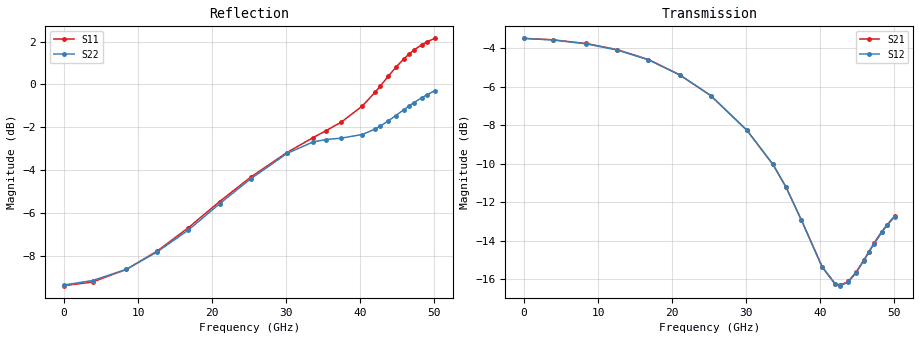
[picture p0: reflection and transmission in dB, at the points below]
! Touchstone file from project
! Exported from ElectronicsDesktop 2025.1.3
# GHz S MA R 50.000000
! Terminal data exported
! Port[1] = Port1
! Port[2] = Port2
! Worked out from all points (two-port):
!   144 points, 10 MHz to 50.05 GHz, reference 50 ohm
!   highest |S21| = -3.50 dB at 10 MHz (marker M1); lowest = -16.3 dB at 42.7 GHz (marker M2)
!   |S21| within 3 dB of the highest: start of sweep to 25.31 GHz
!   lowest |S11| = -9.4 dB at 10 MHz (marker M3), VSWR 2.02, Z = 101 - j0.545 ohm
!   |S11| at or under -10 dB: nowhere
!   |S22| runs from -9.4 to -0.3 dB; largest |S21 - S12| = 0.0023
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0.01  0.3384 -0.4  0.6686 -5.8  0.6682 -6.0  0.3396 0.2
! Gamma 0 0 0 0
! Port Impedance 50 0 50 0
3.85945  0.3452 -1.3  0.663 -10.2  0.6623 -10.3  0.3479 -0.2
8.4088  0.3693 -3.1  0.6484 -19.0  0.647 -18.9  0.3694 -1.7
12.6082  0.408 -4.8  0.6249 -28.5  0.6234 -28.5  0.4062 -2.7
16.8076  0.4625 -7.4  0.5891 -38.2  0.5881 -38.3  0.4568 -4.8
21.007  0.5323 -11.0  0.5378 -48.1  0.5375 -48.1  0.526 -8.3
25.2064  0.607 -16.4  0.475 -57.9  0.4751 -57.9  0.6016 -13.2
30.1057  0.6933 -23.9  0.3857 -67.9  0.3858 -67.9  0.6897 -21.0
33.6052  0.7508 -29.4  0.3147 -73.1  0.3146 -73.1  0.7335 -26.8
35.35495  0.7793 -32.1  0.2752 -74.1  0.2751 -74.2  0.7434 -29.7
37.45465  0.8169 -35.2  0.2256 -72.0  0.2253 -72.1  0.7492 -32.9
40.25425  0.8898 -39.1  0.1706 -59.6  0.1702 -59.7  0.7638 -36.6
42.004  0.9591 -40.8  0.1543 -46.6  0.1537 -46.7  0.7866 -38.5
42.7039  0.9918 -41.1  0.153 -41.0  0.1524 -41.1  0.7992 -38.9
43.75375  1.044 -40.7  0.1563 -32.9  0.1556 -33.0  0.8213 -39.0
44.8036  1.097 -39.3  0.1651 -26.0  0.1643 -26.1  0.8462 -38.2
45.85345  1.147 -36.7  0.1775 -21.1  0.1766 -21.2  0.8724 -36.4
46.55335  1.177 -34.3  0.1868 -19.2  0.186 -19.2  0.8899 -34.6
47.25325  1.204 -31.5  0.1965 -18.2  0.1956 -18.3  0.907 -32.4
48.3031  1.239 -26.7  0.2106 -18.6  0.2097 -18.7  0.9313 -28.6
49.003  1.258 -23.2  0.2194 -19.9  0.2185 -20.0  0.9463 -25.8
50.05285  1.282 -17.7  0.2313 -23.1  0.2303 -23.1  0.9669 -21.3
